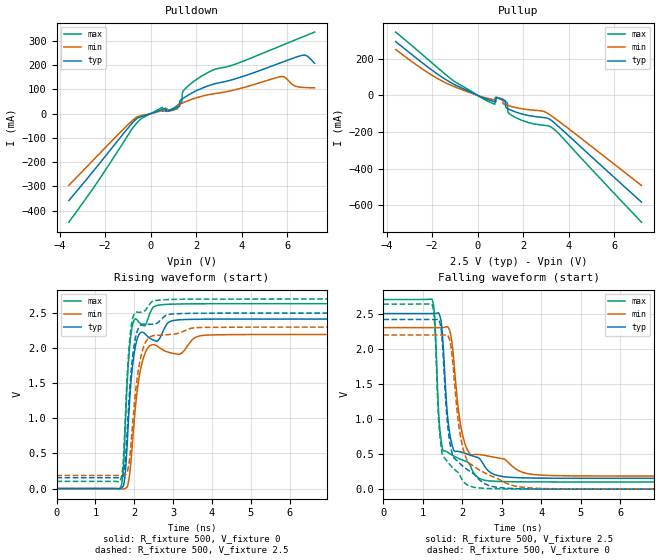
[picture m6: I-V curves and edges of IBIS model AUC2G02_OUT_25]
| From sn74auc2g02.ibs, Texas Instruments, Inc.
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[Model]   AUC2G02_OUT_25
Model_type  Output
Vref =   0
Rref =   500
Cref =   30p
Vmeas =   1.25
| variable   typ   min   max
C_comp   7.45pF   0.27pF   23.62pF
| C_pullup   8.36pF   0.27pF   23.62pF
| C_pulldown   6.53pF   1.89pF   15.75pF
[Temperature Range]   40   100   -40
| Ambient temperature   25   85   -40
[Voltage range]   2.5   2.3   2.7
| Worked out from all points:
|   slope of the pulldown table from 0 to 0.375 V, typ, clamps not added: 30.9 ohm
|   slope of the pullup table from 0 to 0.375 V, typ, clamps not added: 19.2 ohm
|   rising waveform, R_fixture 500, V_fixture 0: 20-80 % time 199ps typ, 264ps min, 156ps max; typ from 0 V to 2.42 V
|   falling waveform, R_fixture 500, V_fixture 2.5: 20-80 % time 229ps typ, 314ps min, 158ps max; typ from 2.5 V to 0.154 V
|   rising waveform, R_fixture 500, V_fixture 2.5: 20-80 % time 197ps typ, 259ps min, 154ps max; typ from 0.154 V to 2.5 V
|   falling waveform, R_fixture 500, V_fixture 0: 20-80 % time 242ps typ, 334ps min, 161ps max; typ from 2.42 V to 0 V
[Pulldown]
| AUC2G02_OUT_25
|   Voltage   I(typ)   I(min)   I(max)
-3.6V     -357.9mA   -295mA     -446.9mA
-445mV    -13.39mA   -9.086mA   -23.04mA
515mV     17.02mA    12.57mA    25.99mA
1.03V     19.04mA    15.49mA    23.85mA
1.27V     29.99mA    38.36mA    41.3mA
1.37V     59.29mA    42.41mA    48.87mA
1.395V    60.81mA    43.42mA    85.06mA
1.48V     65.92mA    46.77mA    98.72mA
2.545V    114.8mA    77.91mA    170.6mA
5.695V    208.4mA    151.5mA    277.8mA
6.74V     240.4mA    107.1mA    317.8mA
7.2V      207mA      105.9mA    335.2mA
[Pullup]
| AUC2G02_OUT_25
|   Voltage   I(typ)   I(min)   I(max)
-3.6V     293.6mA    250.5mA    345.5mA
-960mV    55.5mA     44.14mA    71.53mA
730mV     -33.82mA   -24.42mA   -47.21mA
760mV     -34.84mA   -25.13mA   -47.16mA
770mV     -35.18mA   -25.36mA   -13.07mA
1.115V    -23.84mA   -20.26mA   -27.67mA
1.215V    -28.81mA   -50.48mA   -34.67mA
1.295V    -71.05mA   -53.78mA   -40.2mA
1.345V    -74.3mA    -55.73mA   -93.3mA
1.755V    -94.43mA   -68.81mA   -126mA
3.31V     -143.6mA   -118mA     -180.4mA
7.2V      -582.7mA   -491.8mA   -692.5mA
[Ramp]
| AUC2G02_OUT_25
| variable   typ   min   max
dV/dt_r   1.45/2.00E-10   1.32/2.64E-10   1.59/1.58E-10
dV/dt_f   1.41/2.32E-10   1.28/3.18E-10   1.56/1.62E-10
R_load = 500
[Rising Waveform]
| AUC2G02_OUT_25
R_fixture =   500
C_fixture =   0
L_fixture =   0
V_fixture =   0
V_fixture_min = 0
V_fixture_max = 0
|   Time   V(typ)   V(min)   V(max)
0s        9.791nV    28.67nV    1.858nV
1.635ns   -1.144mV   -224.9uV   3.659mV
1.71ns    27.52mV    -6.105mV   215.8mV
1.765ns   186.5mV    920.1uV    816.1mV
1.85ns    958mV      90.9mV     1.787V
1.95ns    1.714V     616.4mV    2.313V
2.205ns   2.229V     1.797V     2.33V
2.6ns     2.103V     2.027V     2.61V
3.345ns   2.409V     2.011V     2.631V
21.7ns    2.416V     2.195V     2.634V
[Falling Waveform]
| AUC2G02_OUT_25
R_fixture =   500
C_fixture =   0
L_fixture =   0
V_fixture =   2.5
V_fixture_min = 2.3
V_fixture_max = 2.7
|   Time   V(typ)   V(min)   V(max)
0s        2.5V       2.3V       2.7V
1.23ns    2.5V       2.3V       2.707V
1.29ns    2.501V     2.3V       2.522V
1.4ns     2.508V     2.3V       1.082V
1.5ns     2.158V     2.301V     563.7mV
1.625ns   1.046V     2.314V     526.2mV
1.765ns   581.9mV    1.945V     478.1mV
2.055ns   512.6mV    668.5mV    404.6mV
2.55ns    338.5mV    482.5mV    129.5mV
21.7ns    154.5mV    186.3mV    102.6mV
[Rising Waveform]
| AUC2G02_OUT_25
R_fixture =   500
C_fixture =   0
L_fixture =   0
V_fixture =   2.5
V_fixture_min = 2.3
V_fixture_max = 2.7
|   Time   V(typ)   V(min)   V(max)
0s        154.5mV    186.3mV    102.6mV
1.635ns   154.4mV    186mV      107.5mV
1.71ns    188.5mV    181.2mV    333mV
1.765ns   362.5mV    194.6mV    929.4mV
1.85ns    1.123V     308.7mV    1.881V
1.94ns    1.782V     794.3mV    2.372V
2.055ns   2.2V       1.482V     2.515V
2.175ns   2.331V     1.887V     2.513V
2.525ns   2.343V     2.183V     2.676V
21.7ns    2.5V       2.3V       2.7V
[Falling Waveform]
| AUC2G02_OUT_25
R_fixture =   500
C_fixture =   0
L_fixture =   0
V_fixture =   0
V_fixture_min = 0
V_fixture_max = 0
|   Time   V(typ)   V(min)   V(max)
0s        2.416V     2.195V     2.634V
1.23ns    2.416V     2.195V     2.636V
1.29ns    2.415V     2.195V     2.439V
1.395ns   2.421V     2.195V     1.04V
1.49ns    2.11V      2.195V     502.6mV
1.61ns    1.018V     2.196V     401mV
1.73ns    533.5mV    1.95V      321.1mV
1.965ns   351.6mV    717.6mV    163.5mV
2.27ns    224.4mV    333.3mV    30.11mV
21.7ns    20.33uV    1.99uV     10.06uV
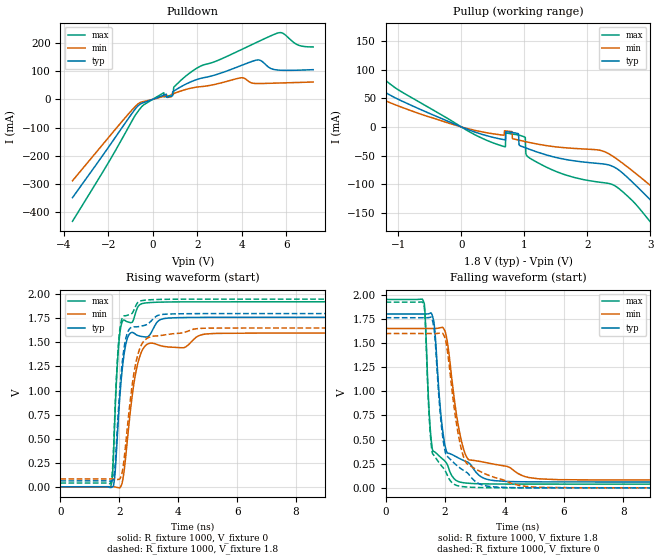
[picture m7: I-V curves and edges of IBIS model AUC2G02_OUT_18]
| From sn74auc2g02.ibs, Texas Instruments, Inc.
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[Model]   AUC2G02_OUT_18
Model_type  Output
Vref =   0
Rref =   1000
Cref =   30p
Vmeas =   0.9
| variable   typ   min   max
C_comp   6.69pF   0.25pF   21.38pF
| C_pullup   7.14pF   1.04pF   21.38pF
| C_pulldown   6.24pF   0.25pF   15.43pF
[Temperature Range]   40   100   -40
| Ambient temperature   25   85   -40
[Voltage range]   1.8   1.65   1.95
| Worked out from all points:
|   slope of the pulldown table from 0 to 0.27 V, typ, clamps not added: 34.4 ohm
|   slope of the pullup table from 0 to 0.27 V, typ, clamps not added: 24.7 ohm
|   rising waveform, R_fixture 1000, V_fixture 0: 20-80 % time 278ps typ, 405ps min, 189ps max; typ from 0 V to 1.76 V
|   falling waveform, R_fixture 1000, V_fixture 1.8: 20-80 % time 322ps typ, 477ps min, 203ps max; typ from 1.8 V to 0.061 V
|   rising waveform, R_fixture 1000, V_fixture 1.8: 20-80 % time 273ps typ, 397ps min, 186ps max; typ from 0.061 V to 1.8 V
|   falling waveform, R_fixture 1000, V_fixture 0: 20-80 % time 330ps typ, 487ps min, 202ps max; typ from 1.76 V to 0 V
[Pulldown]
| AUC2G02_OUT_18
|   Voltage   I(typ)   I(min)   I(max)
-3.6V     -347.6mA   -287.8mA   -431.2mA
-830mV    -38.94mA   -28.94mA   -62.22mA
-405mV    -11.33mA   -7.446mA   -19.55mA
495mV     14.95mA    10.62mA    23.51mA
885mV     12.26mA    19.06mA    15.87mA
925mV     28.54mA    20.16mA    16.88mA
960mV     30.1mA     21.15mA    44.31mA
2.045V    71.87mA    43.99mA    113.3mA
3.92V     118.2mA    75.85mA    173.7mA
4.625V    138.4mA    55.98mA    200.1mA
5.58V     103.9mA    57.6mA     233.8mA
7.2V      105mA      61.31mA    185.3mA
[Pullup]
| AUC2G02_OUT_18
|   Voltage   I(typ)   I(min)   I(max)
-3.6V     267.6mA    221.5mA    318.7mA
-2.61V    174.3mA    138.3mA    219.8mA
-2.13V    131.5mA    101.8mA    171.7mA
110mV     -4.812mA   -3.244mA   -7.318mA
695mV     -22.64mA   -6.826mA   -34.84mA
705mV     -8.168mA   -6.941mA   -10.57mA
980mV     -34.9mA    -24.66mA   -16.5mA
1.11V     -40.21mA   -27.81mA   -56.13mA
2.25V     -64.62mA   -42.31mA   -97.29mA
3.1V      -138.6mA   -111.4mA   -179.7mA
3.915V    -230.4mA   -188mA     -289.7mA
7.2V      -598mA     -503.3mA   -721.1mA
[Ramp]
| AUC2G02_OUT_18
| variable   typ   min   max
dV/dt_r   1.06/2.79E-10   0.97/4.07E-10   1.16/1.90E-10
dV/dt_f   1.05/3.30E-10   0.95/4.81E-10   1.15/2.07E-10
R_load = 1000
[Rising Waveform]
| AUC2G02_OUT_18
R_fixture =   1000
C_fixture =   0
L_fixture =   0
V_fixture =   0
V_fixture_min = 0
V_fixture_max = 0
|   Time   V(typ)   V(min)   V(max)
0s        7.669nV    26.14nV    1.117nV
1.7ns     -4.955mV   615uV      -597.7uV
1.77ns    70.48uV    296.1uV    138.4mV
1.845ns   109.5mV    -1.475mV   692.3mV
2.045ns   1.047V     1.276mV    1.653V
2.295ns   1.562V     556.3mV    1.712V
2.525ns   1.59V      1.131V     1.782V
2.775ns   1.561V     1.417V     1.904V
3.885ns   1.756V     1.449V     1.921V
22.22ns   1.761V     1.597V     1.922V
[Falling Waveform]
| AUC2G02_OUT_18
R_fixture =   1000
C_fixture =   0
L_fixture =   0
V_fixture =   1.8
V_fixture_min = 1.65
V_fixture_max = 1.95
|   Time   V(typ)   V(min)   V(max)
0s        1.8V       1.65V      1.95V
1.27ns    1.8V       1.65V      1.933V
1.33ns    1.8V       1.65V      1.772V
1.475ns   1.804V     1.65V      726.8mV
1.575ns   1.778V     1.65V      395.6mV
1.99ns    448.4mV    1.626V     278.1mV
2.485ns   304mV      576.8mV    61.02mV
2.805ns   257.1mV    289mV      47.17mV
5.145ns   61.88mV    93.65mV    38.82mV
22.22ns   61.07mV    81.21mV    38.69mV
[Rising Waveform]
| AUC2G02_OUT_18
R_fixture =   1000
C_fixture =   0
L_fixture =   0
V_fixture =   1.8
V_fixture_min = 1.65
V_fixture_max = 1.95
|   Time   V(typ)   V(min)   V(max)
0s        61.05mV    81.2mV     38.68mV
1.7ns     56.71mV    81.66mV    39.46mV
1.765ns   64.71mV    81.38mV    162.5mV
1.84ns    175.6mV    80.01mV    702.5mV
1.94ns    658.7mV    75.74mV    1.355V
2.035ns   1.084V     91.63mV    1.675V
2.265ns   1.591V     596.8mV    1.782V
2.72ns    1.669V     1.456V     1.931V
4.85ns    1.8V       1.647V     1.95V
22.22ns   1.8V       1.65V      1.95V
[Falling Waveform]
| AUC2G02_OUT_18
R_fixture =   1000
C_fixture =   0
L_fixture =   0
V_fixture =   0
V_fixture_min = 0
V_fixture_max = 0
|   Time   V(typ)   V(min)   V(max)
0s        1.761V     1.597V     1.922V
1.285ns   1.761V     1.597V     1.888V
1.535ns   1.765V     1.597V     443.6mV
1.64ns    1.616V     1.597V     330.4mV
1.825ns   809.6mV    1.602V     249.3mV
1.97ns    424.3mV    1.571V     195mV
2.41ns    227.9mV    612.7mV    22.98mV
2.745ns   156.8mV    246.5mV    8.531mV
4.74ns    1.253mV    14.35mV    204.6uV
22.22ns   24.22uV    3.92uV     10.57uV
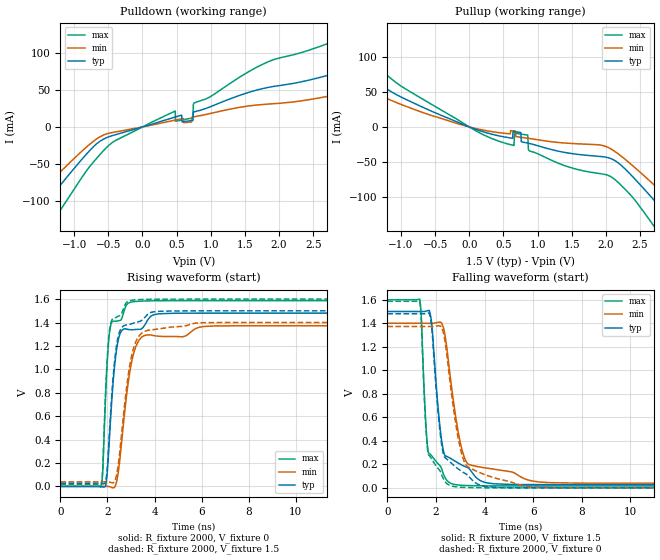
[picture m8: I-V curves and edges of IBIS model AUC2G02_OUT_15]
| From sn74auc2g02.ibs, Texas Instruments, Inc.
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[Model]   AUC2G02_OUT_15
Model_type  Output
Vref =   0
Rref =   2000
Cref =   15p
Vmeas =   0.75
| variable   typ   min   max
C_comp   6.42pF   1.69pF   19.05pF
| C_pullup   6.13pF   1.69pF   19.05pF
| C_pulldown   6.70pF   3.60pF   15.20pF
[Temperature Range]   40   100   -40
| Ambient temperature   25   85   -40
[Voltage range]   1.5   1.4   1.6
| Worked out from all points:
|   slope of the pulldown table from 0 to 0.225 V, typ, clamps not added: 36.6 ohm
|   slope of the pullup table from 0 to 0.225 V, typ, clamps not added: 29.5 ohm
|   rising waveform, R_fixture 2000, V_fixture 0: 20-80 % time 349ps typ, 517ps min, 228ps max; typ from 0 V to 1.48 V
|   falling waveform, R_fixture 2000, V_fixture 1.5: 20-80 % time 405ps typ, 605ps min, 234ps max; typ from 1.5 V to 0.027 V
|   rising waveform, R_fixture 2000, V_fixture 1.5: 20-80 % time 344ps typ, 509ps min, 225ps max; typ from 0.027 V to 1.5 V
|   falling waveform, R_fixture 2000, V_fixture 0: 20-80 % time 406ps typ, 611ps min, 233ps max; typ from 1.48 V to 0 V
[Pulldown]
| AUC2G02_OUT_15
|   Voltage   I(typ)   I(min)   I(max)
-3.6V     -343mA     -284.8mA   -423.7mA
-2.105V   -179.1mA   -144.1mA   -232.4mA
-1.795V   -144.7mA   -115.1mA   -192.1mA
-1.395V   -99.88mA   -78mA      -138.7mA
-395mV    -10.45mA   -6.753mA   -18.28mA
480mV     13.33mA    9.224mA    21.44mA
485mV     13.46mA    9.315mA    7.619mA
735mV     8.724mA    13.39mA    12.06mA
755mV     20.22mA    13.69mA    32.02mA
1.69V     50.03mA    29.61mA    81.13mA
3.34V     86.07mA    49.98mA    134.3mA
7.2V      80.6mA     45.5mA     141.2mA
[Pullup]
| AUC2G02_OUT_15
|   Voltage   I(typ)   I(min)   I(max)
-3.6V     254.2mA    195.1mA    304.8mA
-2.875V   187.5mA    148mA      233.8mA
-2.45V    149.7mA    116.2mA    192.1mA
-1.91V    104.4mA    79.22mA    139.6mA
100mV     -3.652mA   -2.395mA   -5.808mA
650mV     -6.722mA   -5.654mA   -26.6mA
855mV     -23.22mA   -16.17mA   -11.7mA
885mV     -23.88mA   -16.62mA   -34.51mA
2.105V    -46.97mA   -33.55mA   -73.62mA
2.76V     -111.3mA   -88.18mA   -150.1mA
3.36V     -178.2mA   -143.6mA   -230.9mA
7.2V      -605.9mA   -510.3mA   -734mA
[Ramp]
| AUC2G02_OUT_15
| variable   typ   min   max
dV/dt_r   0.89/3.51E-10   0.83/5.23E-10   0.96/2.29E-10
dV/dt_f   0.89/4.10E-10   0.82/6.11E-10   0.95/2.37E-10
R_load = 2000
[Rising Waveform]
| AUC2G02_OUT_15
R_fixture =   2000
C_fixture =   0
L_fixture =   0
V_fixture =   0
V_fixture_min = 0
V_fixture_max = 0
|   Time   V(typ)   V(min)   V(max)
0s        7.042nV    26.32nV    876.9pV
1.725ns   -65.53uV   382.5uV    -5.586mV
1.795ns   -3.923mV   468.3uV    115.6mV
1.94ns    25.28mV    600uV      866.9mV
2.105ns   486.9mV    -2.669mV   1.341V
2.445ns   1.238V     103.2mV    1.415V
2.955ns   1.339V     985.3mV    1.572V
3.51ns    1.358V     1.282V     1.584V
6.11ns    1.48V      1.367V     1.587V
22.22ns   1.481V     1.373V     1.587V
[Falling Waveform]
| AUC2G02_OUT_15
R_fixture =   2000
C_fixture =   0
L_fixture =   0
V_fixture =   1.5
V_fixture_min = 1.4
V_fixture_max = 1.6
|   Time   V(typ)   V(min)   V(max)
0s        1.5V       1.4V       1.6V
1.335ns   1.5V       1.4V       1.605V
1.595ns   1.503V     1.4V       507.5mV
1.725ns   1.509V     1.399V     291.5mV
2.25ns    381.7mV    1.394V     153.4mV
2.67ns    242.1mV    813.3mV    33.99mV
2.99ns    202.5mV    395.8mV    22.92mV
3.3ns     172mV      207mV      19.62mV
5.96ns    27.75mV    58.48mV    16.5mV
22.22ns   27.2mV     38.79mV    16.41mV
[Rising Waveform]
| AUC2G02_OUT_15
R_fixture =   2000
C_fixture =   0
L_fixture =   0
V_fixture =   1.5
V_fixture_min = 1.4
V_fixture_max = 1.6
|   Time   V(typ)   V(min)   V(max)
0s        27.17mV    38.78mV    16.4mV
1.725ns   27.08mV    39.1mV     11.45mV
1.795ns   23.58mV    39.16mV    137.6mV
1.935ns   53.73mV    39.24mV    872.9mV
2.1ns     517.5mV    36.46mV    1.354V
2.425ns   1.251V     140.3mV    1.451V
2.92ns    1.383V     1.001V     1.585V
3.485ns   1.423V     1.314V     1.597V
5.775ns   1.5V       1.395V     1.6V
22.22ns   1.5V       1.4V       1.6V
[Falling Waveform]
| AUC2G02_OUT_15
R_fixture =   2000
C_fixture =   0
L_fixture =   0
V_fixture =   0
V_fixture_min = 0
V_fixture_max = 0
|   Time   V(typ)   V(min)   V(max)
0s        1.481V     1.373V     1.587V
1.335ns   1.48V      1.373V     1.591V
1.59ns    1.483V     1.372V     498.2mV
1.725ns   1.486V     1.372V     275.6mV
2.23ns    374.2mV    1.365V     115.1mV
2.605ns   215.3mV    858.8mV    18.73mV
2.945ns   156.9mV    391.5mV    6.652mV
3.24ns    117.5mV    194.1mV    3.375mV
5.535ns   806.9uV    20.5mV     119.2uV
22.22ns   27.99uV    4.354uV    11.55uV
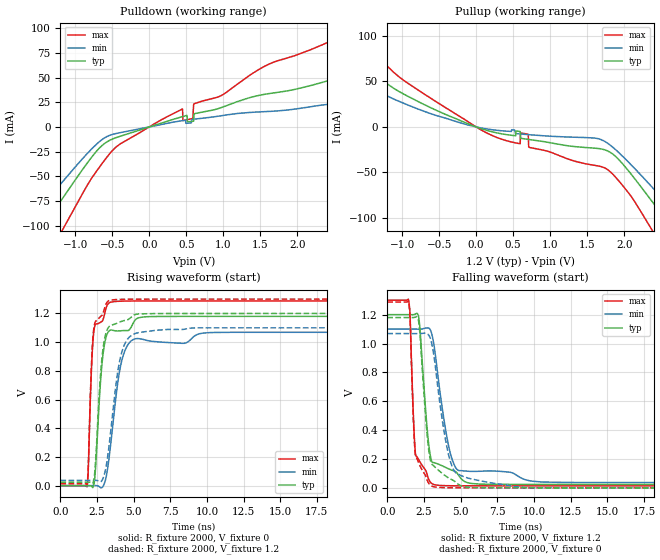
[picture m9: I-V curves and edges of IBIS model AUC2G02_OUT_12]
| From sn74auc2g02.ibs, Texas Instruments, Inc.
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[Model]   AUC2G02_OUT_12
Model_type  Output
Vref =   0
Rref =   2000
Cref =   15p
Vmeas =   0.6
| variable   typ   min   max
C_comp   5.93pF   2.37pF   15.74pF
| C_pullup   5.52pF   2.37pF   15.74pF
| C_pulldown   6.35pF   4.16pF   14.94pF
[Temperature Range]   40   100   -40
| Ambient temperature   25   85   -40
[Voltage range]   1.2   1.1   1.3
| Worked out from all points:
|   slope of the pulldown table from 0 to 0.18 V, typ, clamps not added: 42.3 ohm
|   slope of the pullup table from 0 to 0.18 V, typ, clamps not added: 38.7 ohm
|   rising waveform, R_fixture 2000, V_fixture 0: 20-80 % time 479ps typ, 806ps min, 293ps max; typ from 0 V to 1.18 V
|   falling waveform, R_fixture 2000, V_fixture 1.2: 20-80 % time 557ps typ, 951ps min, 289ps max; typ from 1.2 V to 0.024 V
|   rising waveform, R_fixture 2000, V_fixture 1.2: 20-80 % time 471ps typ, 798ps min, 286ps max; typ from 0.024 V to 1.2 V
|   falling waveform, R_fixture 2000, V_fixture 0: 20-80 % time 555ps typ, 958ps min, 289ps max; typ from 1.18 V to 0 V
[Pulldown]
| AUC2G02_OUT_12
|   Voltage   I(typ)   I(min)   I(max)
-3.6V     -338.3mA   -281.2mA   -417.3mA
-1.81V    -142.4mA   -113.5mA   -188.2mA
-1.485V   -106.7mA   -83.68mA   -145.8mA
-1.225V   -78.14mA   -60.24mA   -111.4mA
-715mV    -24.74mA   -17.64mA   -45.05mA
-390mV    -9.376mA   -5.759mA   -17.06mA
450mV     10.5mA     6.398mA    18.24mA
590mV     5.848mA    7.731mA    8.546mA
605mV     12.96mA    7.861mA    23.36mA
2.86V     55.94mA    19.09mA    100.7mA
3.425V    44.57mA    20.08mA    119.3mA
7.2V      57.06mA    26.82mA    108mA
[Pullup]
| AUC2G02_OUT_12
|   Voltage   I(typ)   I(min)   I(max)
-3.6V     224.6mA    100.8mA    291.5mA
-2.7V     158.6mA    66.17mA    205.2mA
-2.11V    110.3mA    77.88mA    148.7mA
-1.68V    77.88mA    55.75mA    108.7mA
-1.025V   38.18mA    27.56mA    53.97mA
50mV      -1.427mA   -842.9uA   -2.489mA
700mV     -13.68mA   -8.451mA   -7.891mA
1.78V     -26.5mA    -18.1mA    -47.09mA
2.4V      -84.34mA   -68.12mA   -116.4mA
2.695V    -116.7mA   -94.74mA   -156.1mA
3.045V    -155.5mA   -127mA     -202.8mA
7.2V      -615.6mA   -521.5mA   -745mA
[Ramp]
| AUC2G02_OUT_12
| variable   typ   min   max
dV/dt_r   0.72/4.87E-10   0.65/8.15E-10   0.78/2.96E-10
dV/dt_f   0.71/5.62E-10   0.64/9.58E-10   0.78/2.98E-10
R_load = 2000
[Rising Waveform]
| AUC2G02_OUT_12
R_fixture =   2000
C_fixture =   0
L_fixture =   0
V_fixture =   0
V_fixture_min = 0
V_fixture_max = 0
|   Time   V(typ)   V(min)   V(max)
0s        6.587nV    27.93nV    705.3pV
1.82ns    337.3uV    136.3uV    -8.034mV
1.9ns     416.4uV    204.4uV    112.2mV
2.115ns   -4.219mV   439uV      805.5mV
2.255ns   -3.471mV   637.6uV    1.052V
2.85ns    862.2mV    -12.12mV   1.145V
3.33ns    1.079V     201.9mV    1.274V
4.11ns    1.079V     837.4mV    1.286V
4.995ns   1.138V     1.02V      1.287V
23.22ns   1.18V      1.069V     1.287V
[Falling Waveform]
| AUC2G02_OUT_12
R_fixture =   2000
C_fixture =   0
L_fixture =   0
V_fixture =   1.2
V_fixture_min = 1.1
V_fixture_max = 1.3
|   Time   V(typ)   V(min)   V(max)
0s        1.2V       1.1V       1.3V
1.455ns   1.2V       1.1V       1.298V
1.55ns    1.2V       1.1V       1.19V
1.87ns    1.202V     1.1V       298.2mV
2.11ns    1.197V     1.099V     200.2mV
2.755ns   364.1mV    1.109V     77.12mV
3.08ns    175.2mV    1.045V     26.87mV
4.105ns   135.2mV    326.8mV    15mV
4.825ns   92.02mV    121.7mV    14.22mV
23.22ns   24.01mV    36.66mV    13.87mV
[Rising Waveform]
| AUC2G02_OUT_12
R_fixture =   2000
C_fixture =   0
L_fixture =   0
V_fixture =   1.2
V_fixture_min = 1.1
V_fixture_max = 1.3
|   Time   V(typ)   V(min)   V(max)
0s        23.98mV    36.64mV    13.86mV
1.82ns    24.25mV    36.76mV    7.948mV
2.105ns   20.8mV     36.94mV    810.7mV
2.235ns   21.74mV    37.02mV    1.055V
2.375ns   136.2mV    37.09mV    1.141V
2.83ns    884.2mV    35.4mV     1.187V
3.295ns   1.105V     258.5mV    1.289V
4.075ns   1.141V     884.7mV    1.298V
5.03ns    1.19V      1.058V     1.3V
23.22ns   1.2V       1.1V       1.3V
[Falling Waveform]
| AUC2G02_OUT_12
R_fixture =   2000
C_fixture =   0
L_fixture =   0
V_fixture =   0
V_fixture_min = 0
V_fixture_max = 0
|   Time   V(typ)   V(min)   V(max)
0s        1.18V      1.069V     1.287V
1.45ns    1.18V      1.069V     1.286V
1.55ns    1.18V      1.069V     1.169V
1.855ns   1.181V     1.069V     301.9mV
2.11ns    1.167V     1.068V     179.8mV
2.71ns    370.9mV    1.067V     54.62mV
3.005ns   167.3mV    1.01V      13.3mV
4.12ns    72.23mV    253.6mV    981.6uV
5ns       15.45mV    86.37mV    262.2uV
23.22ns   31.68uV    8.14uV     12.28uV
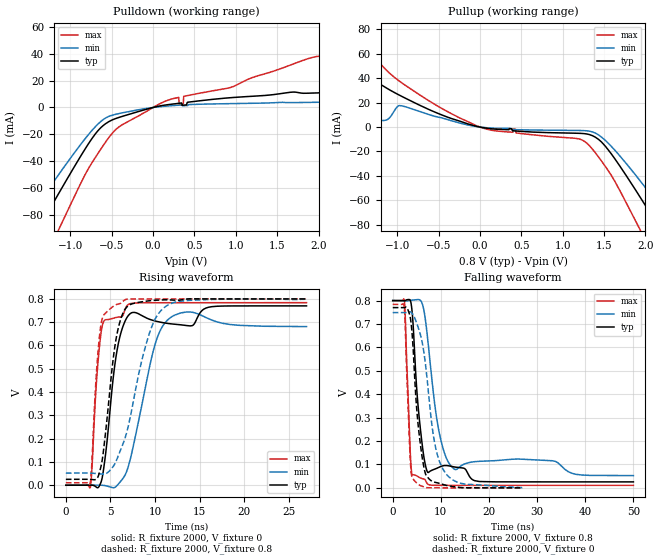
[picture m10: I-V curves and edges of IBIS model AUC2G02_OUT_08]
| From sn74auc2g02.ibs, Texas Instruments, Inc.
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[Model]   AUC2G02_OUT_08
Model_type  Output
Vref =   0
Rref =   2000
Cref =   15p
Vmeas =   0.4
| variable   typ   min   max
C_comp   5.67pF   2.72pF   7.64pF
| C_pullup   5.14pF   2.72pF   7.64pF
| C_pulldown   6.20pF   5.44pF   6.81pF
[Temperature Range]   40   100   -40
| Ambient temperature   25   85   -40
[Voltage range]   0.8   0.8   0.8
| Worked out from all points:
|   slope of the pulldown table from 0 to 0.12 V, typ, clamps not added: 77.1 ohm
|   slope of the pullup table from 0 to 0.12 V, typ, clamps not added: 92.8 ohm
|   rising waveform, R_fixture 2000, V_fixture 0: 20-80 % time 1.41ns typ, 2.22ns min, 821ps max; typ from 0 V to 0.77 V
|   falling waveform, R_fixture 2000, V_fixture 0.8: 20-80 % time 1.77ns typ, 2.84ns min, 869ps max; typ from 0.8 V to 0.025 V
|   rising waveform, R_fixture 2000, V_fixture 0.8: 20-80 % time 1.4ns typ, 2.72ns min, 768ps max; typ from 0.025 V to 0.8 V
|   falling waveform, R_fixture 2000, V_fixture 0: 20-80 % time 1.78ns typ, 2.84ns min, 863ps max; typ from 0.77 V to 0 V
[Pulldown]
| AUC2G02_OUT_08
|   Voltage   I(typ)   I(min)   I(max)
-3.6V     -332mA     -277.5mA   -406.5mA
-1.635V   -117.5mA   -94.15mA   -155.2mA
-1.375V   -89.26mA   -70.66mA   -121.5mA
-1.155V   -65.6mA    -51.21mA   -92.88mA
-630mV    -14.96mA   -10.34mA   -30.86mA
-430mV    -7.788mA   -4.786mA   -15.33mA
-90mV     -1.494mA   -794.3uA   -3.292mA
210mV     2.329mA    1.254mA    6.027mA
365mV     1.692mA    1.285mA    2.781mA
1.98V     10.83mA    3.867mA    38.03mA
2.365V    11.74mA    4.199mA    33.49mA
7.2V      23.85mA    8.894mA    59.33mA
[Pullup]
| AUC2G02_OUT_08
|   Voltage   I(typ)   I(min)   I(max)
-3.6V     79.74mA    9.11mA     185.5mA
-3.08V    78.24mA    9.441mA    162.7mA
-1.59V    27.55mA    11.02mA    82.8mA
-1.305V   38.33mA    6.645mA    59.6mA
-1.13V    31.97mA    5.759mA    46.58mA
-975mV    26.17mA    17.62mA    37.64mA
-245mV    4.854mA    3.296mA    7.479mA
1.36V     -7.061mA   -3.966mA   -18.08mA
1.875V    -50.9mA    -38.75mA   -76.11mA
2.115V    -76.5mA    -59.54mA   -107.8mA
2.405V    -108mA     -85.49mA   -146mA
7.2V      -633.7mA   -537.1mA   -765.1mA
[Ramp]
| AUC2G02_OUT_08
| variable   typ   min   max
dV/dt_r   0.47/1.43E-09   0.45/2.52E-09   0.48/8.25E-10
dV/dt_f   0.47/1.77E-09   0.45/2.85E-09   0.48/8.76E-10
R_load = 2000
[Rising Waveform]
| AUC2G02_OUT_08
R_fixture =   2000
C_fixture =   0
L_fixture =   0
V_fixture =   0
V_fixture_min = 0
V_fixture_max = 0
|   Time   V(typ)   V(min)   V(max)
0s        8.079nV    45.62nV    527.9pV
2.755ns   506.7uV    483.3uV    -8.099mV
3.605ns   -10.69mV   417.2uV    528.7mV
4.365ns   106.2mV    -1.391mV   709.1mV
5.73ns    576.6mV    -1.692mV   721mV
7.21ns    736.7mV    109.1mV    779.5mV
9.93ns    706mV      594.5mV    783.5mV
11.67ns   693.5mV    717.6mV    783.6mV
16.37ns   766.6mV    709mV      783.7mV
27ns      770mV      681.1mV    783.7mV
[Falling Waveform]
| AUC2G02_OUT_08
R_fixture =   2000
C_fixture =   0
L_fixture =   0
V_fixture =   0.8
V_fixture_min = 0.8
V_fixture_max = 0.8
|   Time   V(typ)   V(min)   V(max)
0s        800mV      800mV      800mV
2.425ns   798.8mV    799.7mV    799.6mV
3.64ns    801.4mV    800.4mV    153.2mV
4.025ns   752.3mV    801.8mV    56.45mV
5.425ns   315.1mV    804.1mV    45.8mV
7.29ns    65.71mV    629.9mV    15.64mV
9.69ns    88.66mV    233mV      10.72mV
12.76ns   89.46mV    80.35mV    10.65mV
18.01ns   27.05mV    113.3mV    10.63mV
50ns      25.5mV     52.37mV    10.6mV
[Rising Waveform]
| AUC2G02_OUT_08
R_fixture =   2000
C_fixture =   0
L_fixture =   0
V_fixture =   0.8
V_fixture_min = 0.8
V_fixture_max = 0.8
|   Time   V(typ)   V(min)   V(max)
0s        25.46mV    52.25mV    10.6mV
2.74ns    25.24mV    52.17mV    10.51mV
3.4ns     26.04mV    50.26mV    465.6mV
3.845ns   66.28mV    48.8mV     664.8mV
5.145ns   487.2mV    72.6mV     763mV
5.815ns   663.7mV    120.3mV    777.4mV
6.685ns   758.1mV    208mV      797.1mV
9.12ns    790.8mV    621.3mV    799.8mV
10.93ns   795.8mV    759.8mV    799.9mV
27ns      799.9mV    798.6mV    800mV
[Falling Waveform]
| AUC2G02_OUT_08
R_fixture =   2000
C_fixture =   0
L_fixture =   0
V_fixture =   0
V_fixture_min = 0
V_fixture_max = 0
|   Time   V(typ)   V(min)   V(max)
0s        770mV      748.6mV    783.8mV
2.405ns   769.7mV    748.5mV    770.2mV
3.655ns   726.5mV    751.7mV    115.4mV
4.325ns   563.7mV    736.7mV    35.34mV
5.215ns   282.4mV    689.3mV    16.62mV
6.655ns   71.18mV    552.6mV    2.69mV
8.59ns    24.81mV    205.8mV    123.6uV
10.71ns   12.97mV    70.76mV    62.39uV
14.38ns   998.3uV    18.33mV    36.92uV
27ns      58.04uV    887.4uV    16.02uV
